VERSION 5.7 ;
  NOWIREEXTENSIONATPIN ON ;
  DIVIDERCHAR "/" ;
  BUSBITCHARS "[]" ;
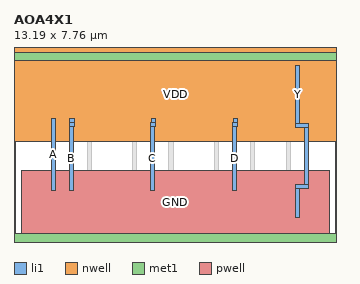
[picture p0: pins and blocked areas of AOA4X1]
MACRO AOA4X1
  CLASS CORE ;
  FOREIGN AOA4X1 ;
  ORIGIN 0.000 0.000 ;
  SIZE 13.190 BY 7.760 ;
  SYMMETRY X Y ;
  SITE unitrh ;
  PIN Y
    DIRECTION OUTPUT ;
    USE SIGNAL ;
    ANTENNADIFFAREA 0.771900 ;
    PORT
      LAYER li1 ;
        RECT 11.510 4.845 11.680 7.200 ;
        RECT 11.510 4.675 12.045 4.845 ;
        RECT 11.875 2.345 12.045 4.675 ;
        RECT 11.505 2.175 12.045 2.345 ;
        RECT 11.505 1.020 11.675 2.175 ;
    END
  END Y
  PIN A
    DIRECTION INPUT ;
    USE SIGNAL ;
    ANTENNAGATEAREA 1.033250 ;
    PORT
      LAYER li1 ;
        RECT 1.515 2.095 1.685 5.045 ;
    END
  END A
  PIN B
    DIRECTION INPUT ;
    USE SIGNAL ;
    ANTENNAGATEAREA 1.027250 ;
    PORT
      LAYER li1 ;
        RECT 2.285 4.890 2.455 5.045 ;
        RECT 2.255 4.715 2.455 4.890 ;
        RECT 2.255 2.095 2.425 4.715 ;
    END
  END B
  PIN C
    DIRECTION INPUT ;
    USE SIGNAL ;
    ANTENNAGATEAREA 1.026450 ;
    PORT
      LAYER li1 ;
        RECT 5.620 4.890 5.790 5.050 ;
        RECT 5.585 4.720 5.790 4.890 ;
        RECT 5.585 2.095 5.755 4.720 ;
    END
  END C
  PIN D
    DIRECTION INPUT ;
    USE SIGNAL ;
    ANTENNAGATEAREA 1.027250 ;
    PORT
      LAYER li1 ;
        RECT 8.945 4.890 9.115 5.045 ;
        RECT 8.915 4.715 9.115 4.890 ;
        RECT 8.915 2.095 9.085 4.715 ;
    END
  END D
  PIN VDD
    DIRECTION INOUT ;
    USE POWER ;
    SHAPE ABUTMENT ;
    PORT
      LAYER nwell ;
        RECT 0.010 4.110 13.190 7.945 ;
      LAYER met1 ;
        RECT 0.010 7.410 13.190 7.760 ;
    END
  END VDD
  PIN GND
    DIRECTION INOUT ;
    USE GROUND ;
    SHAPE ABUTMENT ;
    PORT
      LAYER pwell ;
        RECT 0.320 0.350 12.870 2.900 ;
        RECT 0.000 0.000 13.190 0.350 ;
      LAYER met1 ;
        RECT 0.000 0.000 13.190 0.350 ;
    END
  END GND
  OBS
      LAYER li1 ;
        RECT 0.010 7.410 13.190 7.760 ;
        RECT 0.320 4.290 0.660 7.410 ;
        RECT 1.195 5.315 1.365 7.410 ;
        RECT 1.635 5.465 1.805 7.200 ;
        RECT 2.075 5.735 2.245 7.410 ;
        RECT 2.515 5.465 2.685 7.200 ;
        RECT 2.955 5.735 3.125 7.410 ;
        RECT 1.635 5.295 3.165 5.465 ;
        RECT 0.320 0.350 0.660 2.900 ;
        RECT 1.100 1.845 1.270 1.925 ;
        RECT 2.070 1.845 2.240 1.925 ;
        RECT 2.995 1.920 3.165 5.295 ;
        RECT 3.650 4.290 3.990 7.410 ;
        RECT 4.525 5.475 4.695 7.205 ;
        RECT 4.965 5.735 5.135 7.410 ;
        RECT 5.405 7.005 6.455 7.175 ;
        RECT 5.405 5.475 5.575 7.005 ;
        RECT 4.525 5.305 5.575 5.475 ;
        RECT 5.845 5.475 6.015 6.745 ;
        RECT 6.285 5.735 6.455 7.005 ;
        RECT 5.845 5.305 6.495 5.475 ;
        RECT 4.690 4.890 4.860 5.050 ;
        RECT 4.690 4.720 5.015 4.890 ;
        RECT 1.100 1.675 2.240 1.845 ;
        RECT 1.100 0.545 1.270 1.675 ;
        RECT 1.585 0.350 1.755 1.300 ;
        RECT 2.070 0.795 2.240 1.675 ;
        RECT 2.555 1.750 3.165 1.920 ;
        RECT 2.555 1.015 2.725 1.750 ;
        RECT 3.040 0.795 3.210 1.565 ;
        RECT 2.070 0.625 3.210 0.795 ;
        RECT 2.070 0.545 2.240 0.625 ;
        RECT 3.040 0.545 3.210 0.625 ;
        RECT 3.650 0.350 3.990 2.900 ;
        RECT 4.845 2.095 5.015 4.720 ;
        RECT 4.430 0.795 4.600 1.925 ;
        RECT 6.325 1.920 6.495 5.305 ;
        RECT 6.980 4.290 7.320 7.410 ;
        RECT 7.855 5.315 8.025 7.410 ;
        RECT 8.295 5.465 8.465 7.200 ;
        RECT 8.735 5.735 8.905 7.410 ;
        RECT 9.175 5.465 9.345 7.200 ;
        RECT 9.615 5.735 9.785 7.410 ;
        RECT 8.295 5.295 9.825 5.465 ;
        RECT 4.915 1.750 6.495 1.920 ;
        RECT 4.915 1.015 5.085 1.750 ;
        RECT 5.400 0.795 5.570 1.570 ;
        RECT 5.885 1.015 6.055 1.750 ;
        RECT 6.370 0.795 6.540 1.570 ;
        RECT 4.430 0.625 6.540 0.795 ;
        RECT 4.430 0.350 4.600 0.625 ;
        RECT 4.915 0.350 5.085 0.625 ;
        RECT 5.400 0.350 5.570 0.625 ;
        RECT 5.885 0.350 6.055 0.625 ;
        RECT 6.370 0.350 6.540 0.625 ;
        RECT 6.980 0.350 7.320 2.900 ;
        RECT 8.175 2.095 8.345 5.045 ;
        RECT 7.760 1.845 7.930 1.925 ;
        RECT 8.730 1.845 8.900 1.925 ;
        RECT 9.655 1.920 9.825 5.295 ;
        RECT 10.310 4.290 10.650 7.410 ;
        RECT 11.070 5.365 11.240 7.410 ;
        RECT 11.950 5.365 12.120 7.410 ;
        RECT 7.760 1.675 8.900 1.845 ;
        RECT 7.760 0.545 7.930 1.675 ;
        RECT 8.245 0.350 8.415 1.300 ;
        RECT 8.730 0.795 8.900 1.675 ;
        RECT 9.215 1.750 9.825 1.920 ;
        RECT 9.215 1.015 9.385 1.750 ;
        RECT 9.700 0.795 9.870 1.565 ;
        RECT 8.730 0.625 9.870 0.795 ;
        RECT 8.730 0.545 8.900 0.625 ;
        RECT 9.700 0.545 9.870 0.625 ;
        RECT 10.310 0.350 10.650 2.900 ;
        RECT 11.135 2.100 11.305 5.045 ;
        RECT 12.530 4.290 12.870 7.410 ;
        RECT 11.025 0.800 11.195 1.930 ;
        RECT 11.995 0.800 12.165 1.930 ;
        RECT 11.025 0.630 12.165 0.800 ;
        RECT 11.025 0.350 11.195 0.630 ;
        RECT 11.510 0.350 11.680 0.630 ;
        RECT 11.995 0.350 12.165 0.630 ;
        RECT 12.530 0.350 12.870 2.900 ;
        RECT 0.000 0.000 13.190 0.350 ;
      LAYER mcon ;
        RECT 0.775 7.495 0.945 7.665 ;
        RECT 1.145 7.495 1.315 7.665 ;
        RECT 1.515 7.495 1.685 7.665 ;
        RECT 1.885 7.495 2.055 7.665 ;
        RECT 2.255 7.495 2.425 7.665 ;
        RECT 2.625 7.495 2.795 7.665 ;
        RECT 2.995 7.495 3.165 7.665 ;
        RECT 3.365 7.495 3.535 7.665 ;
        RECT 4.105 7.495 4.275 7.665 ;
        RECT 4.475 7.495 4.645 7.665 ;
        RECT 4.845 7.495 5.015 7.665 ;
        RECT 5.215 7.495 5.385 7.665 ;
        RECT 5.585 7.495 5.755 7.665 ;
        RECT 5.955 7.495 6.125 7.665 ;
        RECT 6.325 7.495 6.495 7.665 ;
        RECT 6.695 7.495 6.865 7.665 ;
        RECT 7.435 7.495 7.605 7.665 ;
        RECT 7.805 7.495 7.975 7.665 ;
        RECT 8.175 7.495 8.345 7.665 ;
        RECT 8.545 7.495 8.715 7.665 ;
        RECT 8.915 7.495 9.085 7.665 ;
        RECT 9.285 7.495 9.455 7.665 ;
        RECT 9.655 7.495 9.825 7.665 ;
        RECT 10.025 7.495 10.195 7.665 ;
        RECT 10.765 7.495 10.935 7.665 ;
        RECT 11.135 7.495 11.305 7.665 ;
        RECT 11.505 7.495 11.675 7.665 ;
        RECT 11.875 7.495 12.045 7.665 ;
        RECT 12.245 7.495 12.415 7.665 ;
        RECT 2.995 2.685 3.165 2.855 ;
        RECT 4.845 2.685 5.015 2.855 ;
        RECT 6.325 2.685 6.495 2.855 ;
        RECT 8.175 2.685 8.345 2.855 ;
        RECT 9.655 2.685 9.825 2.855 ;
        RECT 11.135 2.685 11.305 2.855 ;
        RECT 0.775 0.095 0.945 0.265 ;
        RECT 1.145 0.095 1.315 0.265 ;
        RECT 1.515 0.095 1.685 0.265 ;
        RECT 1.885 0.095 2.055 0.265 ;
        RECT 2.255 0.095 2.425 0.265 ;
        RECT 2.625 0.095 2.795 0.265 ;
        RECT 2.995 0.095 3.165 0.265 ;
        RECT 3.365 0.095 3.535 0.265 ;
        RECT 4.105 0.095 4.275 0.265 ;
        RECT 4.475 0.095 4.645 0.265 ;
        RECT 4.845 0.095 5.015 0.265 ;
        RECT 5.215 0.095 5.385 0.265 ;
        RECT 5.585 0.095 5.755 0.265 ;
        RECT 5.955 0.095 6.125 0.265 ;
        RECT 6.325 0.095 6.495 0.265 ;
        RECT 6.695 0.095 6.865 0.265 ;
        RECT 7.435 0.095 7.605 0.265 ;
        RECT 7.805 0.095 7.975 0.265 ;
        RECT 8.175 0.095 8.345 0.265 ;
        RECT 8.545 0.095 8.715 0.265 ;
        RECT 8.915 0.095 9.085 0.265 ;
        RECT 9.285 0.095 9.455 0.265 ;
        RECT 9.655 0.095 9.825 0.265 ;
        RECT 10.025 0.095 10.195 0.265 ;
        RECT 10.765 0.095 10.935 0.265 ;
        RECT 11.135 0.095 11.305 0.265 ;
        RECT 11.505 0.095 11.675 0.265 ;
        RECT 11.875 0.095 12.045 0.265 ;
        RECT 12.245 0.095 12.415 0.265 ;
      LAYER met1 ;
        RECT 2.965 2.855 3.195 2.885 ;
        RECT 4.815 2.855 5.045 2.885 ;
        RECT 6.295 2.855 6.525 2.885 ;
        RECT 8.145 2.855 8.375 2.885 ;
        RECT 9.625 2.855 9.855 2.885 ;
        RECT 11.105 2.855 11.335 2.885 ;
        RECT 2.935 2.685 5.075 2.855 ;
        RECT 6.265 2.685 8.405 2.855 ;
        RECT 9.595 2.685 11.365 2.855 ;
        RECT 2.965 2.655 3.195 2.685 ;
        RECT 4.815 2.655 5.045 2.685 ;
        RECT 6.295 2.655 6.525 2.685 ;
        RECT 8.145 2.655 8.375 2.685 ;
        RECT 9.625 2.655 9.855 2.685 ;
        RECT 11.105 2.655 11.335 2.685 ;
  END
END AOA4X1
END LIBRARY

